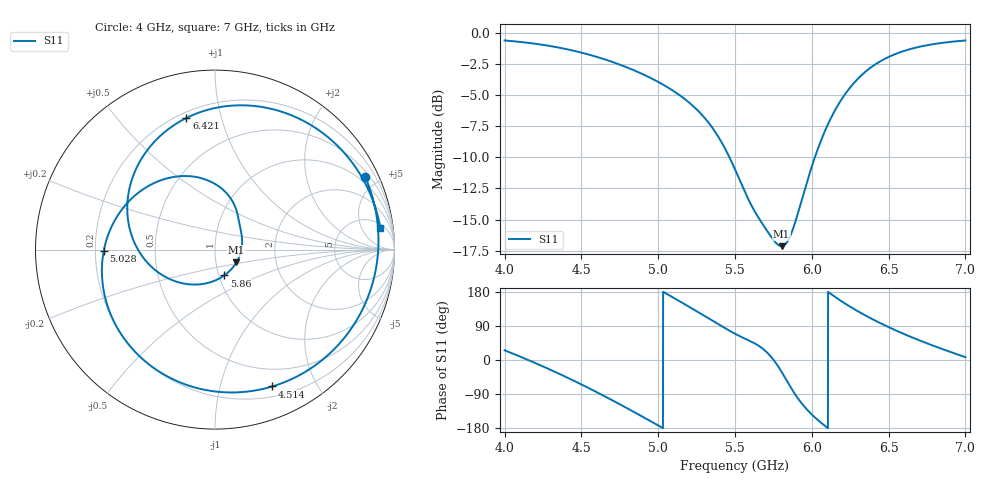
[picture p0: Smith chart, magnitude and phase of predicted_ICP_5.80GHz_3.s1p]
! ICP-predicted S11, target max centred GHz at -10 dB. Complex ensemble mean (passive and causal);
! its |S11| can differ slightly from the dB-domain mean reported in designs.csv.
!  Air_gap = 4.21mm
!  W_Patch = 14.22mm
!  L_Patch = 17.66mm
!  Sx = 3.36mm
!  Sy = 1.8mm
!  W_Patch1 = 8.15mm
!  WS = 0.89mm
!  Curve_Amp1 = 0.95mm
!  Extra = 6.36mm
# GHz S MA R 50
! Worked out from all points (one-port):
!   3001 points, 4 GHz to 7 GHz, reference 50 ohm
!   lowest |S11| = -17.1 dB at 5.803 GHz (marker M1), VSWR 1.32, Z = 62.8 - j9.2 ohm
!   |S11| at or under -10 dB: 5.464 GHz to 6.02 GHz (556.3 MHz wide, 9.69 % of centre)
!   S11 on the Smith chart (normalised r, x): 4 GHz: 0.72, +4.28; 4.514 GHz: 0.30, -1.46; 5.028 GHz: 0.23, -0.01; 5.86 GHz: 1.06, -0.31; 6.421 GHz: 0.23, +0.78; 7 GHz: 7, +12
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4  0.9295 25.6
4.191  0.9032 -6.5
4.282  0.886 -22.8
4.375  0.865 -40.1
4.514  0.8266 -67.3
4.631  0.7881 -91.4
4.75  0.7436 -116.8
4.893  0.6837 -148.5
5.028  0.6203 -179.1
5.125  0.5689 158.4
5.218  0.5134 136.4
5.305  0.4528 115.4
5.412  0.3638 89.4
5.5  0.2829 69.3
5.645  0.1844 39.9
5.803  0.1392 -31.1
5.86  0.153 -70.4
5.875  0.1616 -80.3
5.958  0.2391 -125.9
6.038  0.3398 -157.9
6.148  0.4839 167.5
6.25  0.6027 140.5
6.328  0.6783 122.2
6.421  0.7505 102.3
6.52  0.8084 83.0
6.625  0.8529 64.4
6.817  0.9035 33.8
7  0.9291 7.5
